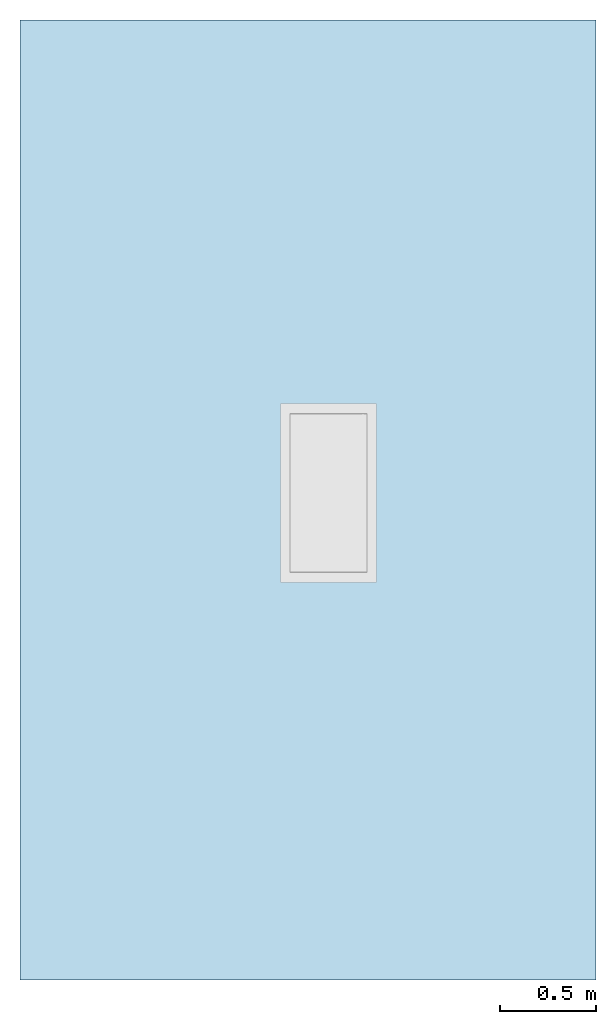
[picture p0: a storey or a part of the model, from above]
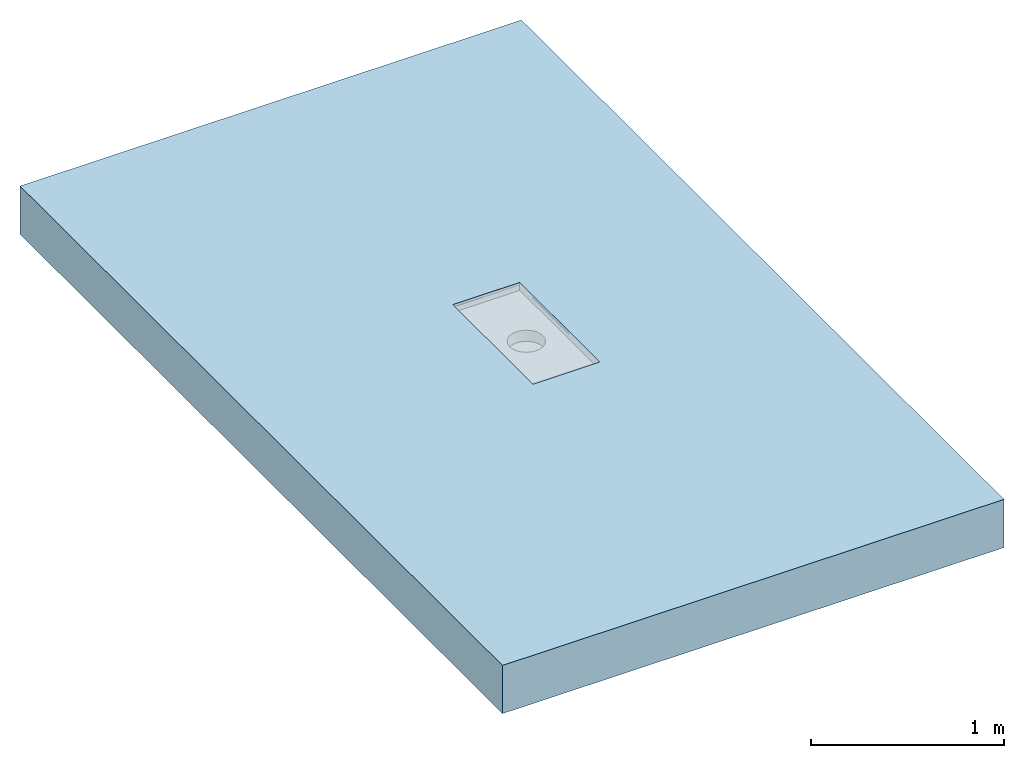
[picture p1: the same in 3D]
Properties of the parts of a building model (IFC2X3)

# File
Description: ViewDefinition [CoordinationView]
File name: Project Number
Time: 2016-11-22T09:56:33
Written by: The EXPRESS Data Manager Version 5.01.0100.02.64mod : 6 Jun 2012
Made in: 20130308_1515(x64) - Exporter 2014.0.2013.0308 - Default UI
Comment: STEP Physical File produced by: The EXPRESS Data Manager Version 5.01.0100.02.64mod : 6 Jun 2012 * Module: EDMstepFileFactory/EDMstandAlone * Creation date: Tue Nov 22 09:56:33 2016 * Host: IN-BLR-PC-0012 * Database: C:\Users\pakumar\AppData\Local\Temp\{68832475-DD36-43CB-BCE8-5673DF4A8990}\ifc * Database version: 5507 * Database creation date: Tue Nov 22 09:56:33 2016 * Schema: IFC2X3 * Model: DataRepository.ifc * Model creation date: Tue Nov 22 09:56:33 2016 * Header model: DataRepository.ifc_HeaderModel * Header model creation date: Tue Nov 22 09:56:33 2016 * EDMuser: sdai-user * EDMgroup: sdai-group * License ID and type: 5605 : Permanent license. Expiry date: * EDMstepFileFactory options: 020000

# IfcProject, Project Number
LongName: Project Name; Phase: Project Status

# IfcSite, Default
RefLatitude: 42, 21, 30, 344238; RefLongitude: -71, -3, -35, -194702; RefElevation: 0 mm

# IfcBuilding
Pset_BuildingCommon - NumberOfStoreys: 1
Other - Client Name: Owner; Project Status: Project Status; Project Address: Enter address here; Project Name: Project Name; Project Issue Date: Issue Date; Project Number: Project Number

# IfcBuildingStorey, Level 1
LongName: Level 1; Elevation: 0 mm
Constraints - Elevation Base: Project Base Point; Elevation: 0 mm
Graphics - Line Pattern: Grid Line 1/2"; Symbol: Level Head - Circle: Level Head - Circle; Symbol at End 2 Default: yes; Line Weight: 1; Color: 0; Symbol at End 1 Default: no
Dimensions - Computation Height: 0 mm
Identity Data - Structural: no; Name: Level 1; Building Story: yes

# IfcFlowTerminal: 416743 - Hygienic Extended Channel - with Gully 218 - 800mm LG - 400mm Wide, ACO Tray Channel - Hygienic - Extended - 400mm Wide:416743 - Hygienic Extended Channel - with Gully 218 - 800mm LG - 400mm Wide:427585
In: Level 1
Material: Stainless Steel AISI 304, Stainless Steel AISI 304 - Grating
Construction - Detail - Outlet 200: yes; Detail - Outlet 142mm: no; Grating: yes; 416868 - 368 x 398mm - Mesh Grating - L15 - Stainless Steel 1.4301: yes; 416870 - 368 x 598mm - Mesh Grating - L15 - Stainless Steel 1.4301: no; 416820 - 368 x 398mm - Ladder Grating - R50 - Stainless Steel 1.4301: no; 416826 - 368 x 598mm - Ladder Grating - M125 - Stainless Steel 1.4301: no; 416822 - 368 x 598mm - Ladder Grating - R50 - Stainless Steel 1.4301: no; 416824 - 368 x 398mm - Ladder Grating - M125 - Stainless Steel 1.4301: no; 416888 - 368 x 398mm - Mesh Grating - L15 - Stainless Steel 1.4301: no; 416890 - 368 x 598mm - Mesh Grating - L15 - Stainless Steel 1.4301: no
Mechanical - System Classification: Sanitary
Identity Data - Mark: 26; Fax: +44 (0)1462 851490; Cost: 0; Address: ACO Business Centre, Caxton Road, Bedford, MK41 0LF; Watermark1: This file is the property of ACO Technologies PLC.; Watermarked With: BIM Manager Premium Suite.; Website: www.acobd.com; Watermarked By: www.acobd.com; E-mail Sales: abdcommercial@aco.co.uk; Telephone: +44 (0)1462 816666; E-mail Technical: abdtechnical@aco.co.uk; Watermark2: This file is water marked and users are prohibited to reproduce, adapt, distribute this information.; Manufacturer: ACO Building Drainage
Constraints - Level: Level: Level 1
Phasing - Phase Created: New Construction
Pset_ManufacturerTypeInformation - Manufacturer: ACO Building Drainage
Dimensions - End Connection Plate Start: -770 mm; Depth: 29 mm; Number of gratings: 2; End Connection Plate End: -800 mm; Spigot Distance: 400 mm; Endplate Position: 800 mm; End Plate: 800 mm; Outlet: 200 mm; Floor Cut Void Height: 62.8 mm; Inside Outlet Rad: 98 mm; x: -815 mm; Grating Height: 21 mm; Grating Void Cut Length: 500 mm; Outside Outlet Rad: 100 mm; Invert Depth: 50 mm; Length Channel: -770 mm; Grating Length: 499 mm
General - Channel Recyclable: Fully recyclable; Installation guidelines: http://issuu.com/acobuildingdrainage/docs/aco_hygiene_first_catalogue/17?e=0; Weight (Kg): 7.9; Channel Material: Stainless steel 1.4301 (EN 10088); Foul air trap seal Colour: Black; Product Type: Extended Kitchen Tray Channel; Channel Recycled material content: 20 - 30 %; Outlet Diameter (mm): 200; Foul air trap Recyclable: Fully recyclable; Load Class: A15 - C250 (EN 1253); Product Range: ACO Hygiene First; Price: POA - contact ACO; Maintenance guidelines: http://issuu.com/acobuildingdrainage/docs/aco_hygiene_first_catalogue/17?e=0; Product Code: 416743; Product Description: ACO Hygiene First Extended Kitchen Tray Channel 400 x 830 / 200 Dia Outlet & Foul Air Trap; Channel Dimension: 400 x 830; Foul air trap seal Material: NBR; Foul air trap Recycled material content: 0%; Product Standard: EN 1253 / EN 1672 / EN ISO 14159; Channel Colour: passivated stainless steel surface ( matt grey)
Model Properties - Grating Product Code 416870: N/A; Grating Product Code 416824: Load Class M 125 (EN 1253) - Ladder Grate - Stainless steel 1.4301 (EN 10088) - 368 x 398 - 9.4kg; Grating Product Code 416888: Load Class L 15 (EN 1253) - Mesh Grate - Stainless steel 1.4301 (EN 10088) - 368 x 398 - 4.1kg; Grating Product Code 416868: Load Class L 15 (EN 1253) - Mesh Grate - Stainless steel 1.4301 (EN 10088) - 368 x 398 - 4.0kg; Grating Product Code 416820: Load Class R 50 (EN 1253) - Ladder Grate - Stainless steel 1.4301 (EN 10088) - 368 x 398 - 6.9kg; Grating Product Code 416826: N/A; Grating Product Code 416822: N/A; Grating Product Code 416890: N/A
Other - Hygienic Standard Channel - 400mm LG - 400mm Wide: no; Hygienic Standard Channel - 800mm LG - 400mm Wide: yes; Flow: 0.155385 m3/s; Spigot Outlets Channels: yes; Number mesh: 17; Invert Depth Detail: 51.5 mm; Hygienic Standard Channel - 600mm LG - 400mm Wide: no

# IfcOpeningElement: Recess
In: Level 1
Phasing - Phase Created: New Construction
Structural - Enable Analytical Model: no; Structural: no
Constraints - Height Offset From Level: 0 mm; Related to Mass: no; Level: Level: Level 1; Room Bounding: yes
Dimensions - Area: 161.459 ft2; Volume: 160.787 ft3; Thickness: 304.8 mm; Perimeter: 16000 mm
Identity Data - Assembly Description: Floor Construction; Assembly Code: B1010
Analytical Properties - Roughness: 3; Absorptance: 0.7
Construction - Function: Interior; Default Thickness: 304.8 mm
Graphics - Coarse Scale Fill Color: 0

# IfcSlab: Floor:Generic - 12", Floor:Generic - 12":184145
In: Level 1
PredefinedType: FLOOR; Material: Default Floor 304.8 mm
Phasing - Phase Created: New Construction
Structural - Enable Analytical Model: no; Structural: no
Constraints - Height Offset From Level: 0 mm; Related to Mass: no; Level: Level: Level 1; Room Bounding: yes
Dimensions - Area: 161.459 ft2; Volume: 160.787 ft3; Thickness: 304.8 mm; Perimeter: 16000 mm
Pset_SlabCommon - Reference: Generic - 12"; IsExternal: no; LoadBearing: yes
Identity Data - Assembly Description: Floor Construction; Assembly Code: B1010
Analytical Properties - Roughness: 3; Absorptance: 0.7
Construction - Function: Interior; Default Thickness: 304.8 mm
Graphics - Coarse Scale Fill Color: 0
